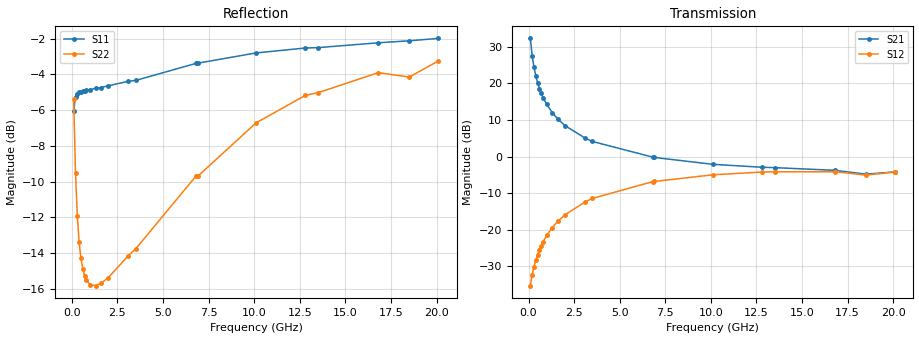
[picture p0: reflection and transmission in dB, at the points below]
!  Infineon Technologies AG
! BFR380L3 , PF131585-7, No.6, Th 09.10.01, soldered on pcb-board, measured with PP GSG850
!  Vce=1.5 V,  Ic=60.0 mA
! Common Emitter S-Parameters:  15. November 2001
#  GHz  S  MA  R  50
! f  S11  S21  S12  S22
! GHz  Mag  Ang  Mag  Ang  Mag  Ang  Mag  Ang
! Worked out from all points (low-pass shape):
!   201 points, 100 MHz to 20.1 GHz, reference 50 ohm
!   highest |S21| = 32.25 dB at 100 MHz (marker M1); lowest = -4.8 dB at 18.5 GHz (marker M2)
!   |S21| within 3 dB of the highest: start of sweep to 163.6 MHz
!   lowest |S11| = -6.1 dB at 100 MHz (marker M3), VSWR 2.99, Z = 21.5 - j24.6 ohm
!   |S11| at or under -10 dB: nowhere
!   |S22| runs from -15.8 to -3.3 dB; largest |S21 - S12| = 41
!   S11 on the Smith chart (normalised r, x): 100 MHz: 0.43, -0.49; 500 MHz: 0.28, -0.05; 3.1 GHz: 0.28, +0.34; 6.9 GHz: 0.33, +0.81; 12.8 GHz: 0.52, +1.54; 20.1 GHz: 0.99, +2.61
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0.1  0.4981 -120.2  40.97 125.2  0.0173 56.4  0.5374 -65.5
0.2  0.546 -149.1  23.81 107.3  0.02444 57.5  0.3344 -92.8
0.3  0.5568 -161.3  16.47 99.6  0.03154 62.1  0.2528 -108.7
0.4  0.562 -168.1  12.53 94.7  0.03856 64.8  0.2138 -120.0
0.5  0.5627 -173.2  10.09 91.1  0.04591 67.3  0.1928 -128.5
0.6  0.5677 -176.7  8.441 88.3  0.0535 68.6  0.1802 -135.2
0.7  0.568 -179.8  7.269 85.9  0.06102 69.5  0.1726 -140.6
0.8  0.5704 177.6  6.376 83.6  0.06883 70.1  0.1675 -145.0
1  0.5708 173.0  5.131 79.7  0.08425 70.4  0.1628 -151.7
1.3  0.5769 167.2  3.979 74.4  0.1073 69.8  0.1617 -158.7
1.6  0.5794 161.9  3.262 69.5  0.1304 68.6  0.1642 -163.8
2  0.586 155.5  2.645 63.5  0.1605 66.2  0.1704 -169.1
3.1  0.6033 139.9  1.786 48.4  0.2402 58.6  0.1962 179.3
3.5  0.6066 134.6  1.607 43.4  0.2683 55.6  0.205 176.1
6.8  0.6769 99.4  0.9839 11.4  0.4541 30.9  0.3273 144.0
6.9  0.6778 98.6  0.9721 10.6  0.4575 30.1  0.3271 143.2
10.1  0.7242 75.5  0.7836 -8.7  0.5633 9.0  0.4615 117.6
12.8  0.7475 61.9  0.7141 -21.1  0.6148 -7.3  0.5508 97.2
13.5  0.7494 58.6  0.7056 -23.7  0.6193 -11.2  0.5606 93.1
16.8  0.773 46.6  0.6486 -34.4  0.6206 -26.4  0.6379 73.9
18.5  0.783 45.0  0.5758 -41.9  0.5591 -34.7  0.62 69.1
20.1  0.7954 37.6  0.6166 -45.4  0.6131 -39.7  0.6878 58.9
